VERSION 5.7 ;
  NOWIREEXTENSIONATPIN ON ;
  DIVIDERCHAR "/" ;
  BUSBITCHARS "[]" ;
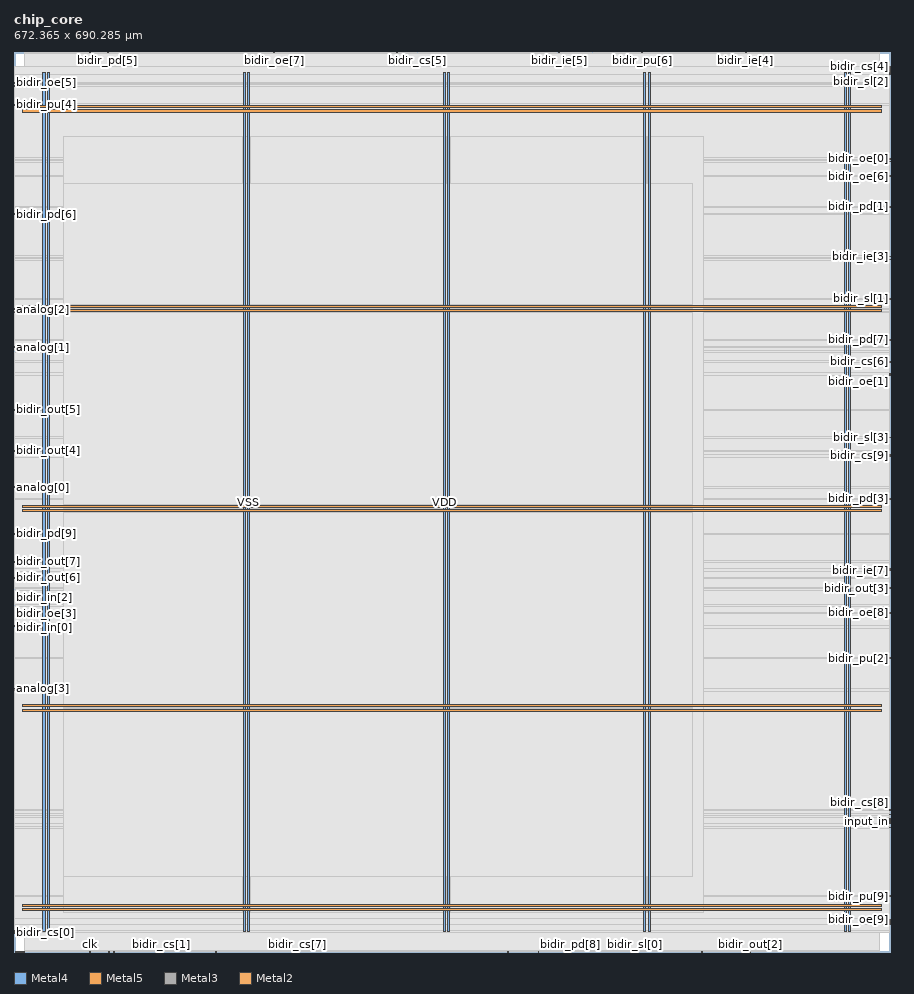
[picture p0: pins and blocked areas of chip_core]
MACRO chip_core
  CLASS BLOCK ;
  FOREIGN chip_core ;
  ORIGIN 0.000 0.000 ;
  SIZE 672.365 BY 690.285 ;
  PIN VDD
    DIRECTION INOUT ;
    USE POWER ;
    PORT
      LAYER Metal4 ;
        RECT 22.240 15.380 23.840 674.540 ;
    END
    PORT
      LAYER Metal4 ;
        RECT 175.840 15.380 177.440 674.540 ;
    END
    PORT
      LAYER Metal4 ;
        RECT 329.440 15.380 331.040 674.540 ;
    END
    PORT
      LAYER Metal4 ;
        RECT 483.040 15.380 484.640 674.540 ;
    END
    PORT
      LAYER Metal4 ;
        RECT 636.640 15.380 638.240 674.540 ;
    END
    PORT
      LAYER Metal5 ;
        RECT 6.720 31.530 665.280 33.130 ;
    END
    PORT
      LAYER Metal5 ;
        RECT 6.720 184.710 665.280 186.310 ;
    END
    PORT
      LAYER Metal5 ;
        RECT 6.720 337.890 665.280 339.490 ;
    END
    PORT
      LAYER Metal5 ;
        RECT 6.720 491.070 665.280 492.670 ;
    END
    PORT
      LAYER Metal5 ;
        RECT 6.720 644.250 665.280 645.850 ;
    END
  END VDD
  PIN VSS
    DIRECTION INOUT ;
    USE GROUND ;
    PORT
      LAYER Metal4 ;
        RECT 25.540 15.380 27.140 674.540 ;
    END
    PORT
      LAYER Metal4 ;
        RECT 179.140 15.380 180.740 674.540 ;
    END
    PORT
      LAYER Metal4 ;
        RECT 332.740 15.380 334.340 674.540 ;
    END
    PORT
      LAYER Metal4 ;
        RECT 486.340 15.380 487.940 674.540 ;
    END
    PORT
      LAYER Metal4 ;
        RECT 639.940 15.380 641.540 674.540 ;
    END
    PORT
      LAYER Metal5 ;
        RECT 6.720 34.830 665.280 36.430 ;
    END
    PORT
      LAYER Metal5 ;
        RECT 6.720 188.010 665.280 189.610 ;
    END
    PORT
      LAYER Metal5 ;
        RECT 6.720 341.190 665.280 342.790 ;
    END
    PORT
      LAYER Metal5 ;
        RECT 6.720 494.370 665.280 495.970 ;
    END
    PORT
      LAYER Metal5 ;
        RECT 6.720 647.550 665.280 649.150 ;
    END
  END VSS
  PIN analog[0]
    DIRECTION INOUT ;
    USE SIGNAL ;
    ANTENNAGATEAREA 1.017500 ;
    PORT
      LAYER Metal3 ;
        RECT 0.000 356.160 0.560 356.720 ;
    END
  END analog[0]
  PIN analog[1]
    DIRECTION INOUT ;
    USE SIGNAL ;
    ANTENNAGATEAREA 1.536500 ;
    ANTENNADIFFAREA 0.893200 ;
    PORT
      LAYER Metal3 ;
        RECT 0.000 463.680 0.560 464.240 ;
    END
  END analog[1]
  PIN analog[2]
    DIRECTION INOUT ;
    USE SIGNAL ;
    ANTENNAGATEAREA 0.894500 ;
    ANTENNADIFFAREA 0.893200 ;
    PORT
      LAYER Metal3 ;
        RECT 0.000 492.800 0.560 493.360 ;
    END
  END analog[2]
  PIN analog[3]
    DIRECTION INOUT ;
    USE SIGNAL ;
    ANTENNAGATEAREA 0.894500 ;
    ANTENNADIFFAREA 0.893200 ;
    PORT
      LAYER Metal3 ;
        RECT 0.000 201.600 0.560 202.160 ;
    END
  END analog[3]
  PIN bidir_cs[0]
    DIRECTION OUTPUT ;
    USE SIGNAL ;
    ANTENNADIFFAREA 0.536800 ;
    PORT
      LAYER Metal3 ;
        RECT 0.000 14.560 0.560 15.120 ;
    END
  END bidir_cs[0]
  PIN bidir_cs[1]
    DIRECTION OUTPUT ;
    USE SIGNAL ;
    ANTENNADIFFAREA 0.536800 ;
    PORT
      LAYER Metal2 ;
        RECT 113.120 0.000 113.680 0.560 ;
    END
  END bidir_cs[1]
  PIN bidir_cs[2]
    DIRECTION OUTPUT ;
    USE SIGNAL ;
    ANTENNADIFFAREA 0.536800 ;
    PORT
      LAYER Metal2 ;
        RECT 76.160 0.000 76.720 0.560 ;
    END
  END bidir_cs[2]
  PIN bidir_cs[3]
    DIRECTION OUTPUT ;
    USE SIGNAL ;
    ANTENNADIFFAREA 0.360800 ;
    PORT
      LAYER Metal3 ;
        RECT 671.805 101.920 672.365 102.480 ;
    END
  END bidir_cs[3]
  PIN bidir_cs[4]
    DIRECTION OUTPUT ;
    USE SIGNAL ;
    ANTENNADIFFAREA 0.360800 ;
    PORT
      LAYER Metal3 ;
        RECT 671.805 678.720 672.365 679.280 ;
    END
  END bidir_cs[4]
  PIN bidir_cs[5]
    DIRECTION OUTPUT ;
    USE SIGNAL ;
    ANTENNADIFFAREA 0.360800 ;
    PORT
      LAYER Metal2 ;
        RECT 309.120 689.725 309.680 690.285 ;
    END
  END bidir_cs[5]
  PIN bidir_cs[6]
    DIRECTION OUTPUT ;
    USE SIGNAL ;
    ANTENNADIFFAREA 0.360800 ;
    PORT
      LAYER Metal3 ;
        RECT 671.805 452.480 672.365 453.040 ;
    END
  END bidir_cs[6]
  PIN bidir_cs[7]
    DIRECTION OUTPUT ;
    USE SIGNAL ;
    ANTENNADIFFAREA 0.360800 ;
    PORT
      LAYER Metal2 ;
        RECT 217.280 0.000 217.840 0.560 ;
    END
  END bidir_cs[7]
  PIN bidir_cs[8]
    DIRECTION OUTPUT ;
    USE SIGNAL ;
    ANTENNADIFFAREA 0.360800 ;
    PORT
      LAYER Metal3 ;
        RECT 671.805 108.640 672.365 109.200 ;
    END
  END bidir_cs[8]
  PIN bidir_cs[9]
    DIRECTION OUTPUT ;
    USE SIGNAL ;
    ANTENNADIFFAREA 0.360800 ;
    PORT
      LAYER Metal3 ;
        RECT 671.805 380.800 672.365 381.360 ;
    END
  END bidir_cs[9]
  PIN bidir_ie[0]
    DIRECTION OUTPUT ;
    USE SIGNAL ;
    ANTENNADIFFAREA 0.536800 ;
    PORT
      LAYER Metal3 ;
        RECT 671.805 95.200 672.365 95.760 ;
    END
  END bidir_ie[0]
  PIN bidir_ie[1]
    DIRECTION OUTPUT ;
    USE SIGNAL ;
    ANTENNADIFFAREA 0.536800 ;
    PORT
      LAYER Metal2 ;
        RECT 58.240 689.725 58.800 690.285 ;
    END
  END bidir_ie[1]
  PIN bidir_ie[2]
    DIRECTION OUTPUT ;
    USE SIGNAL ;
    ANTENNADIFFAREA 0.536800 ;
    PORT
      LAYER Metal3 ;
        RECT 671.805 105.280 672.365 105.840 ;
    END
  END bidir_ie[2]
  PIN bidir_ie[3]
    DIRECTION OUTPUT ;
    USE SIGNAL ;
    ANTENNADIFFAREA 0.360800 ;
    PORT
      LAYER Metal3 ;
        RECT 671.805 533.120 672.365 533.680 ;
    END
  END bidir_ie[3]
  PIN bidir_ie[4]
    DIRECTION OUTPUT ;
    USE SIGNAL ;
    ANTENNADIFFAREA 0.360800 ;
    PORT
      LAYER Metal2 ;
        RECT 561.120 689.725 561.680 690.285 ;
    END
  END bidir_ie[4]
  PIN bidir_ie[5]
    DIRECTION OUTPUT ;
    USE SIGNAL ;
    ANTENNADIFFAREA 0.360800 ;
    PORT
      LAYER Metal2 ;
        RECT 417.760 689.725 418.320 690.285 ;
    END
  END bidir_ie[5]
  PIN bidir_ie[6]
    DIRECTION OUTPUT ;
    USE SIGNAL ;
    ANTENNADIFFAREA 0.360800 ;
    PORT
      LAYER Metal2 ;
        RECT 443.520 689.725 444.080 690.285 ;
    END
  END bidir_ie[6]
  PIN bidir_ie[7]
    DIRECTION OUTPUT ;
    USE SIGNAL ;
    ANTENNADIFFAREA 0.360800 ;
    PORT
      LAYER Metal3 ;
        RECT 671.805 292.320 672.365 292.880 ;
    END
  END bidir_ie[7]
  PIN bidir_ie[8]
    DIRECTION OUTPUT ;
    USE SIGNAL ;
    ANTENNADIFFAREA 0.360800 ;
    PORT
      LAYER Metal3 ;
        RECT 671.805 293.440 672.365 294.000 ;
    END
  END bidir_ie[8]
  PIN bidir_ie[9]
    DIRECTION OUTPUT ;
    USE SIGNAL ;
    ANTENNADIFFAREA 0.360800 ;
    PORT
      LAYER Metal3 ;
        RECT 671.805 379.680 672.365 380.240 ;
    END
  END bidir_ie[9]
  PIN bidir_in[0]
    DIRECTION INPUT ;
    USE SIGNAL ;
    ANTENNAGATEAREA 0.498500 ;
    PORT
      LAYER Metal3 ;
        RECT 0.000 248.640 0.560 249.200 ;
    END
  END bidir_in[0]
  PIN bidir_in[1]
    DIRECTION INPUT ;
    USE SIGNAL ;
    ANTENNAGATEAREA 0.498500 ;
    PORT
      LAYER Metal3 ;
        RECT 0.000 249.760 0.560 250.320 ;
    END
  END bidir_in[1]
  PIN bidir_in[2]
    DIRECTION INPUT ;
    USE SIGNAL ;
    ANTENNAGATEAREA 0.498500 ;
    PORT
      LAYER Metal3 ;
        RECT 0.000 277.760 0.560 278.320 ;
    END
  END bidir_in[2]
  PIN bidir_in[3]
    DIRECTION INPUT ;
    USE SIGNAL ;
    PORT
      LAYER Metal2 ;
        RECT 1.120 0.000 1.680 0.560 ;
    END
  END bidir_in[3]
  PIN bidir_in[4]
    DIRECTION INPUT ;
    USE SIGNAL ;
    PORT
      LAYER Metal2 ;
        RECT 2.240 0.000 2.800 0.560 ;
    END
  END bidir_in[4]
  PIN bidir_in[5]
    DIRECTION INPUT ;
    USE SIGNAL ;
    PORT
      LAYER Metal2 ;
        RECT 3.360 0.000 3.920 0.560 ;
    END
  END bidir_in[5]
  PIN bidir_in[6]
    DIRECTION INPUT ;
    USE SIGNAL ;
    PORT
      LAYER Metal2 ;
        RECT 4.480 0.000 5.040 0.560 ;
    END
  END bidir_in[6]
  PIN bidir_in[7]
    DIRECTION INPUT ;
    USE SIGNAL ;
    PORT
      LAYER Metal2 ;
        RECT 5.600 0.000 6.160 0.560 ;
    END
  END bidir_in[7]
  PIN bidir_in[8]
    DIRECTION INPUT ;
    USE SIGNAL ;
    PORT
      LAYER Metal2 ;
        RECT 6.720 0.000 7.280 0.560 ;
    END
  END bidir_in[8]
  PIN bidir_in[9]
    DIRECTION INPUT ;
    USE SIGNAL ;
    PORT
      LAYER Metal2 ;
        RECT 7.840 0.000 8.400 0.560 ;
    END
  END bidir_in[9]
  PIN bidir_oe[0]
    DIRECTION OUTPUT ;
    USE SIGNAL ;
    ANTENNADIFFAREA 0.360800 ;
    PORT
      LAYER Metal3 ;
        RECT 671.805 608.160 672.365 608.720 ;
    END
  END bidir_oe[0]
  PIN bidir_oe[1]
    DIRECTION OUTPUT ;
    USE SIGNAL ;
    ANTENNADIFFAREA 0.360800 ;
    PORT
      LAYER Metal3 ;
        RECT 671.805 443.520 672.365 444.080 ;
    END
  END bidir_oe[1]
  PIN bidir_oe[2]
    DIRECTION OUTPUT ;
    USE SIGNAL ;
    ANTENNADIFFAREA 0.360800 ;
    PORT
      LAYER Metal3 ;
        RECT 671.805 605.920 672.365 606.480 ;
    END
  END bidir_oe[2]
  PIN bidir_oe[3]
    DIRECTION OUTPUT ;
    USE SIGNAL ;
    ANTENNADIFFAREA 0.897600 ;
    PORT
      LAYER Metal3 ;
        RECT 0.000 265.440 0.560 266.000 ;
    END
  END bidir_oe[3]
  PIN bidir_oe[4]
    DIRECTION OUTPUT ;
    USE SIGNAL ;
    ANTENNADIFFAREA 0.536800 ;
    PORT
      LAYER Metal3 ;
        RECT 671.805 674.240 672.365 674.800 ;
    END
  END bidir_oe[4]
  PIN bidir_oe[5]
    DIRECTION OUTPUT ;
    USE SIGNAL ;
    ANTENNADIFFAREA 0.536800 ;
    PORT
      LAYER Metal3 ;
        RECT 0.000 666.400 0.560 666.960 ;
    END
  END bidir_oe[5]
  PIN bidir_oe[6]
    DIRECTION OUTPUT ;
    USE SIGNAL ;
    ANTENNADIFFAREA 0.536800 ;
    PORT
      LAYER Metal3 ;
        RECT 671.805 594.720 672.365 595.280 ;
    END
  END bidir_oe[6]
  PIN bidir_oe[7]
    DIRECTION OUTPUT ;
    USE SIGNAL ;
    ANTENNADIFFAREA 0.536800 ;
    PORT
      LAYER Metal2 ;
        RECT 199.360 689.725 199.920 690.285 ;
    END
  END bidir_oe[7]
  PIN bidir_oe[8]
    DIRECTION OUTPUT ;
    USE SIGNAL ;
    ANTENNADIFFAREA 0.536800 ;
    PORT
      LAYER Metal3 ;
        RECT 671.805 259.840 672.365 260.400 ;
    END
  END bidir_oe[8]
  PIN bidir_oe[9]
    DIRECTION OUTPUT ;
    USE SIGNAL ;
    ANTENNADIFFAREA 0.536800 ;
    PORT
      LAYER Metal3 ;
        RECT 671.805 24.640 672.365 25.200 ;
    END
  END bidir_oe[9]
  PIN bidir_out[0]
    DIRECTION OUTPUT ;
    USE SIGNAL ;
    ANTENNADIFFAREA 0.897600 ;
    PORT
      LAYER Metal3 ;
        RECT 671.805 98.560 672.365 99.120 ;
    END
  END bidir_out[0]
  PIN bidir_out[1]
    DIRECTION OUTPUT ;
    USE SIGNAL ;
    ANTENNADIFFAREA 0.897600 ;
    PORT
      LAYER Metal3 ;
        RECT 671.805 100.800 672.365 101.360 ;
    END
  END bidir_out[1]
  PIN bidir_out[2]
    DIRECTION OUTPUT ;
    USE SIGNAL ;
    ANTENNADIFFAREA 0.897600 ;
    PORT
      LAYER Metal2 ;
        RECT 564.480 0.000 565.040 0.560 ;
    END
  END bidir_out[2]
  PIN bidir_out[3]
    DIRECTION OUTPUT ;
    USE SIGNAL ;
    ANTENNADIFFAREA 0.897600 ;
    PORT
      LAYER Metal3 ;
        RECT 671.805 278.880 672.365 279.440 ;
    END
  END bidir_out[3]
  PIN bidir_out[4]
    DIRECTION OUTPUT ;
    USE SIGNAL ;
    ANTENNADIFFAREA 0.897600 ;
    PORT
      LAYER Metal3 ;
        RECT 0.000 384.160 0.560 384.720 ;
    END
  END bidir_out[4]
  PIN bidir_out[5]
    DIRECTION OUTPUT ;
    USE SIGNAL ;
    ANTENNADIFFAREA 0.897600 ;
    PORT
      LAYER Metal3 ;
        RECT 0.000 415.520 0.560 416.080 ;
    END
  END bidir_out[5]
  PIN bidir_out[6]
    DIRECTION OUTPUT ;
    USE SIGNAL ;
    ANTENNADIFFAREA 0.897600 ;
    PORT
      LAYER Metal3 ;
        RECT 0.000 286.720 0.560 287.280 ;
    END
  END bidir_out[6]
  PIN bidir_out[7]
    DIRECTION OUTPUT ;
    USE SIGNAL ;
    ANTENNADIFFAREA 0.897600 ;
    PORT
      LAYER Metal3 ;
        RECT 0.000 299.040 0.560 299.600 ;
    END
  END bidir_out[7]
  PIN bidir_out[8]
    DIRECTION OUTPUT ;
    USE SIGNAL ;
    ANTENNADIFFAREA 0.897600 ;
    PORT
      LAYER Metal3 ;
        RECT 0.000 490.560 0.560 491.120 ;
    END
  END bidir_out[8]
  PIN bidir_out[9]
    DIRECTION OUTPUT ;
    USE SIGNAL ;
    ANTENNADIFFAREA 0.897600 ;
    PORT
      LAYER Metal3 ;
        RECT 0.000 200.480 0.560 201.040 ;
    END
  END bidir_out[9]
  PIN bidir_pd[0]
    DIRECTION OUTPUT ;
    USE SIGNAL ;
    ANTENNADIFFAREA 0.360800 ;
    PORT
      LAYER Metal2 ;
        RECT 527.520 0.000 528.080 0.560 ;
    END
  END bidir_pd[0]
  PIN bidir_pd[1]
    DIRECTION OUTPUT ;
    USE SIGNAL ;
    ANTENNADIFFAREA 0.360800 ;
    PORT
      LAYER Metal3 ;
        RECT 671.805 571.200 672.365 571.760 ;
    END
  END bidir_pd[1]
  PIN bidir_pd[2]
    DIRECTION OUTPUT ;
    USE SIGNAL ;
    ANTENNADIFFAREA 0.360800 ;
    PORT
      LAYER Metal3 ;
        RECT 671.805 676.480 672.365 677.040 ;
    END
  END bidir_pd[2]
  PIN bidir_pd[3]
    DIRECTION OUTPUT ;
    USE SIGNAL ;
    ANTENNADIFFAREA 0.360800 ;
    PORT
      LAYER Metal3 ;
        RECT 671.805 347.200 672.365 347.760 ;
    END
  END bidir_pd[3]
  PIN bidir_pd[4]
    DIRECTION OUTPUT ;
    USE SIGNAL ;
    ANTENNADIFFAREA 0.360800 ;
    PORT
      LAYER Metal3 ;
        RECT 0.000 460.320 0.560 460.880 ;
    END
  END bidir_pd[4]
  PIN bidir_pd[5]
    DIRECTION OUTPUT ;
    USE SIGNAL ;
    ANTENNADIFFAREA 0.360800 ;
    PORT
      LAYER Metal2 ;
        RECT 71.680 689.725 72.240 690.285 ;
    END
  END bidir_pd[5]
  PIN bidir_pd[6]
    DIRECTION OUTPUT ;
    USE SIGNAL ;
    ANTENNADIFFAREA 0.360800 ;
    PORT
      LAYER Metal3 ;
        RECT 0.000 565.600 0.560 566.160 ;
    END
  END bidir_pd[6]
  PIN bidir_pd[7]
    DIRECTION OUTPUT ;
    USE SIGNAL ;
    ANTENNADIFFAREA 0.360800 ;
    PORT
      LAYER Metal3 ;
        RECT 671.805 469.280 672.365 469.840 ;
    END
  END bidir_pd[7]
  PIN bidir_pd[8]
    DIRECTION OUTPUT ;
    USE SIGNAL ;
    ANTENNADIFFAREA 0.360800 ;
    PORT
      LAYER Metal2 ;
        RECT 426.720 0.000 427.280 0.560 ;
    END
  END bidir_pd[8]
  PIN bidir_pd[9]
    DIRECTION OUTPUT ;
    USE SIGNAL ;
    ANTENNADIFFAREA 0.360800 ;
    PORT
      LAYER Metal3 ;
        RECT 0.000 320.320 0.560 320.880 ;
    END
  END bidir_pd[9]
  PIN bidir_pu[0]
    DIRECTION OUTPUT ;
    USE SIGNAL ;
    ANTENNADIFFAREA 0.536800 ;
    PORT
      LAYER Metal3 ;
        RECT 671.805 23.520 672.365 24.080 ;
    END
  END bidir_pu[0]
  PIN bidir_pu[1]
    DIRECTION OUTPUT ;
    USE SIGNAL ;
    ANTENNADIFFAREA 0.360800 ;
    PORT
      LAYER Metal2 ;
        RECT 402.080 0.000 402.640 0.560 ;
    END
  END bidir_pu[1]
  PIN bidir_pu[2]
    DIRECTION OUTPUT ;
    USE SIGNAL ;
    ANTENNADIFFAREA 0.360800 ;
    PORT
      LAYER Metal3 ;
        RECT 671.805 225.120 672.365 225.680 ;
    END
  END bidir_pu[2]
  PIN bidir_pu[3]
    DIRECTION OUTPUT ;
    USE SIGNAL ;
    ANTENNADIFFAREA 0.360800 ;
    PORT
      LAYER Metal3 ;
        RECT 671.805 675.360 672.365 675.920 ;
    END
  END bidir_pu[3]
  PIN bidir_pu[4]
    DIRECTION OUTPUT ;
    USE SIGNAL ;
    ANTENNADIFFAREA 0.360800 ;
    PORT
      LAYER Metal3 ;
        RECT 0.000 649.600 0.560 650.160 ;
    END
  END bidir_pu[4]
  PIN bidir_pu[5]
    DIRECTION OUTPUT ;
    USE SIGNAL ;
    ANTENNADIFFAREA 0.360800 ;
    PORT
      LAYER Metal2 ;
        RECT 416.640 689.725 417.200 690.285 ;
    END
  END bidir_pu[5]
  PIN bidir_pu[6]
    DIRECTION OUTPUT ;
    USE SIGNAL ;
    ANTENNADIFFAREA 0.360800 ;
    PORT
      LAYER Metal2 ;
        RECT 481.600 689.725 482.160 690.285 ;
    END
  END bidir_pu[6]
  PIN bidir_pu[7]
    DIRECTION OUTPUT ;
    USE SIGNAL ;
    ANTENNADIFFAREA 0.360800 ;
    PORT
      LAYER Metal2 ;
        RECT 293.440 689.725 294.000 690.285 ;
    END
  END bidir_pu[7]
  PIN bidir_pu[8]
    DIRECTION OUTPUT ;
    USE SIGNAL ;
    ANTENNADIFFAREA 0.360800 ;
    PORT
      LAYER Metal2 ;
        RECT 378.560 0.000 379.120 0.560 ;
    END
  END bidir_pu[8]
  PIN bidir_pu[9]
    DIRECTION OUTPUT ;
    USE SIGNAL ;
    ANTENNADIFFAREA 0.360800 ;
    PORT
      LAYER Metal3 ;
        RECT 671.805 42.560 672.365 43.120 ;
    END
  END bidir_pu[9]
  PIN bidir_sl[0]
    DIRECTION OUTPUT ;
    USE SIGNAL ;
    ANTENNADIFFAREA 0.360800 ;
    PORT
      LAYER Metal2 ;
        RECT 476.000 0.000 476.560 0.560 ;
    END
  END bidir_sl[0]
  PIN bidir_sl[1]
    DIRECTION OUTPUT ;
    USE SIGNAL ;
    ANTENNADIFFAREA 0.360800 ;
    PORT
      LAYER Metal3 ;
        RECT 671.805 500.640 672.365 501.200 ;
    END
  END bidir_sl[1]
  PIN bidir_sl[2]
    DIRECTION OUTPUT ;
    USE SIGNAL ;
    ANTENNADIFFAREA 0.360800 ;
    PORT
      LAYER Metal3 ;
        RECT 671.805 673.120 672.365 673.680 ;
    END
  END bidir_sl[2]
  PIN bidir_sl[3]
    DIRECTION OUTPUT ;
    USE SIGNAL ;
    ANTENNADIFFAREA 0.536800 ;
    PORT
      LAYER Metal3 ;
        RECT 671.805 394.240 672.365 394.800 ;
    END
  END bidir_sl[3]
  PIN bidir_sl[4]
    DIRECTION OUTPUT ;
    USE SIGNAL ;
    ANTENNADIFFAREA 0.360800 ;
    PORT
      LAYER Metal3 ;
        RECT 0.000 664.160 0.560 664.720 ;
    END
  END bidir_sl[4]
  PIN bidir_sl[5]
    DIRECTION OUTPUT ;
    USE SIGNAL ;
    ANTENNADIFFAREA 0.360800 ;
    PORT
      LAYER Metal3 ;
        RECT 671.805 677.600 672.365 678.160 ;
    END
  END bidir_sl[5]
  PIN bidir_sl[6]
    DIRECTION OUTPUT ;
    USE SIGNAL ;
    ANTENNADIFFAREA 0.360800 ;
    PORT
      LAYER Metal3 ;
        RECT 671.805 530.880 672.365 531.440 ;
    END
  END bidir_sl[6]
  PIN bidir_sl[7]
    DIRECTION OUTPUT ;
    USE SIGNAL ;
    ANTENNADIFFAREA 0.360800 ;
    PORT
      LAYER Metal2 ;
        RECT 154.560 0.000 155.120 0.560 ;
    END
  END bidir_sl[7]
  PIN bidir_sl[8]
    DIRECTION OUTPUT ;
    USE SIGNAL ;
    ANTENNADIFFAREA 0.360800 ;
    PORT
      LAYER Metal3 ;
        RECT 671.805 21.280 672.365 21.840 ;
    END
  END bidir_sl[8]
  PIN bidir_sl[9]
    DIRECTION OUTPUT ;
    USE SIGNAL ;
    ANTENNADIFFAREA 0.360800 ;
    PORT
      LAYER Metal3 ;
        RECT 671.805 22.400 672.365 22.960 ;
    END
  END bidir_sl[9]
  PIN clk
    DIRECTION INPUT ;
    USE SIGNAL ;
    ANTENNAGATEAREA 4.738000 ;
    PORT
      LAYER Metal2 ;
        RECT 58.240 0.000 58.800 0.560 ;
    END
  END clk
  PIN input_in
    DIRECTION INPUT ;
    USE SIGNAL ;
    ANTENNAGATEAREA 0.498500 ;
    PORT
      LAYER Metal3 ;
        RECT 671.805 99.680 672.365 100.240 ;
    END
  END input_in
  PIN input_pd
    DIRECTION OUTPUT ;
    USE SIGNAL ;
    ANTENNADIFFAREA 0.360800 ;
    PORT
      LAYER Metal3 ;
        RECT 671.805 442.400 672.365 442.960 ;
    END
  END input_pd
  PIN input_pu
    DIRECTION OUTPUT ;
    USE SIGNAL ;
    ANTENNADIFFAREA 0.360800 ;
    PORT
      LAYER Metal3 ;
        RECT 0.000 15.680 0.560 16.240 ;
    END
  END input_pu
  PIN rst_n
    DIRECTION INPUT ;
    USE SIGNAL ;
    ANTENNAGATEAREA 0.498500 ;
    PORT
      LAYER Metal2 ;
        RECT 72.800 0.000 73.360 0.560 ;
    END
  END rst_n
  OBS
      LAYER Nwell ;
        RECT 6.290 15.250 665.710 674.670 ;
      LAYER Metal1 ;
        RECT 6.720 15.380 665.280 674.540 ;
      LAYER Metal2 ;
        RECT 7.980 689.425 57.940 689.725 ;
        RECT 59.100 689.425 71.380 689.725 ;
        RECT 72.540 689.425 199.060 689.725 ;
        RECT 200.220 689.425 293.140 689.725 ;
        RECT 294.300 689.425 308.820 689.725 ;
        RECT 309.980 689.425 416.340 689.725 ;
        RECT 418.620 689.425 443.220 689.725 ;
        RECT 444.380 689.425 481.300 689.725 ;
        RECT 482.460 689.425 560.820 689.725 ;
        RECT 561.980 689.425 663.460 689.725 ;
        RECT 7.980 0.860 663.460 689.425 ;
        RECT 8.700 0.560 57.940 0.860 ;
        RECT 59.100 0.560 72.500 0.860 ;
        RECT 73.660 0.560 75.860 0.860 ;
        RECT 77.020 0.560 112.820 0.860 ;
        RECT 113.980 0.560 154.260 0.860 ;
        RECT 155.420 0.560 216.980 0.860 ;
        RECT 218.140 0.560 378.260 0.860 ;
        RECT 379.420 0.560 401.780 0.860 ;
        RECT 402.940 0.560 426.420 0.860 ;
        RECT 427.580 0.560 475.700 0.860 ;
        RECT 476.860 0.560 527.220 0.860 ;
        RECT 528.380 0.560 564.180 0.860 ;
        RECT 565.340 0.560 663.460 0.860 ;
      LAYER Metal3 ;
        RECT 0.560 672.820 671.505 679.140 ;
        RECT 0.560 667.260 671.805 672.820 ;
        RECT 0.860 666.100 671.805 667.260 ;
        RECT 0.560 665.020 671.805 666.100 ;
        RECT 0.860 663.860 671.805 665.020 ;
        RECT 0.560 650.460 671.805 663.860 ;
        RECT 0.860 649.300 671.805 650.460 ;
        RECT 0.560 609.020 671.805 649.300 ;
        RECT 0.560 607.860 671.505 609.020 ;
        RECT 0.560 606.780 671.805 607.860 ;
        RECT 0.560 605.620 671.505 606.780 ;
        RECT 0.560 595.580 671.805 605.620 ;
        RECT 0.560 594.420 671.505 595.580 ;
        RECT 0.560 572.060 671.805 594.420 ;
        RECT 0.560 570.900 671.505 572.060 ;
        RECT 0.560 566.460 671.805 570.900 ;
        RECT 0.860 565.300 671.805 566.460 ;
        RECT 0.560 533.980 671.805 565.300 ;
        RECT 0.560 532.820 671.505 533.980 ;
        RECT 0.560 531.740 671.805 532.820 ;
        RECT 0.560 530.580 671.505 531.740 ;
        RECT 0.560 501.500 671.805 530.580 ;
        RECT 0.560 500.340 671.505 501.500 ;
        RECT 0.560 493.660 671.805 500.340 ;
        RECT 0.860 492.500 671.805 493.660 ;
        RECT 0.560 491.420 671.805 492.500 ;
        RECT 0.860 490.260 671.805 491.420 ;
        RECT 0.560 470.140 671.805 490.260 ;
        RECT 0.560 468.980 671.505 470.140 ;
        RECT 0.560 464.540 671.805 468.980 ;
        RECT 0.860 463.380 671.805 464.540 ;
        RECT 0.560 461.180 671.805 463.380 ;
        RECT 0.860 460.020 671.805 461.180 ;
        RECT 0.560 453.340 671.805 460.020 ;
        RECT 0.560 452.180 671.505 453.340 ;
        RECT 0.560 444.380 671.805 452.180 ;
        RECT 0.560 442.100 671.505 444.380 ;
        RECT 0.560 416.380 671.805 442.100 ;
        RECT 0.860 415.220 671.805 416.380 ;
        RECT 0.560 395.100 671.805 415.220 ;
        RECT 0.560 393.940 671.505 395.100 ;
        RECT 0.560 385.020 671.805 393.940 ;
        RECT 0.860 383.860 671.805 385.020 ;
        RECT 0.560 381.660 671.805 383.860 ;
        RECT 0.560 379.380 671.505 381.660 ;
        RECT 0.560 357.020 671.805 379.380 ;
        RECT 0.860 355.860 671.805 357.020 ;
        RECT 0.560 348.060 671.805 355.860 ;
        RECT 0.560 346.900 671.505 348.060 ;
        RECT 0.560 321.180 671.805 346.900 ;
        RECT 0.860 320.020 671.805 321.180 ;
        RECT 0.560 299.900 671.805 320.020 ;
        RECT 0.860 298.740 671.805 299.900 ;
        RECT 0.560 294.300 671.805 298.740 ;
        RECT 0.560 292.020 671.505 294.300 ;
        RECT 0.560 287.580 671.805 292.020 ;
        RECT 0.860 286.420 671.805 287.580 ;
        RECT 0.560 279.740 671.805 286.420 ;
        RECT 0.560 278.620 671.505 279.740 ;
        RECT 0.860 278.580 671.505 278.620 ;
        RECT 0.860 277.460 671.805 278.580 ;
        RECT 0.560 266.300 671.805 277.460 ;
        RECT 0.860 265.140 671.805 266.300 ;
        RECT 0.560 260.700 671.805 265.140 ;
        RECT 0.560 259.540 671.505 260.700 ;
        RECT 0.560 250.620 671.805 259.540 ;
        RECT 0.860 248.340 671.805 250.620 ;
        RECT 0.560 225.980 671.805 248.340 ;
        RECT 0.560 224.820 671.505 225.980 ;
        RECT 0.560 202.460 671.805 224.820 ;
        RECT 0.860 200.180 671.805 202.460 ;
        RECT 0.560 109.500 671.805 200.180 ;
        RECT 0.560 108.340 671.505 109.500 ;
        RECT 0.560 106.140 671.805 108.340 ;
        RECT 0.560 104.980 671.505 106.140 ;
        RECT 0.560 102.780 671.805 104.980 ;
        RECT 0.560 98.260 671.505 102.780 ;
        RECT 0.560 96.060 671.805 98.260 ;
        RECT 0.560 94.900 671.505 96.060 ;
        RECT 0.560 43.420 671.805 94.900 ;
        RECT 0.560 42.260 671.505 43.420 ;
        RECT 0.560 25.500 671.805 42.260 ;
        RECT 0.560 20.980 671.505 25.500 ;
        RECT 0.560 16.540 671.805 20.980 ;
        RECT 0.860 14.700 671.805 16.540 ;
      LAYER Metal4 ;
        RECT 38.220 30.330 175.540 625.430 ;
        RECT 177.740 30.330 178.840 625.430 ;
        RECT 181.040 30.330 329.140 625.430 ;
        RECT 331.340 30.330 332.440 625.430 ;
        RECT 334.640 30.330 482.740 625.430 ;
        RECT 484.940 30.330 486.040 625.430 ;
        RECT 488.240 30.330 529.060 625.430 ;
      LAYER Metal5 ;
        RECT 38.140 496.570 520.180 589.270 ;
        RECT 38.140 493.270 520.180 493.770 ;
        RECT 38.140 343.390 520.180 490.470 ;
        RECT 38.140 340.090 520.180 340.590 ;
        RECT 38.140 190.210 520.180 337.290 ;
        RECT 38.140 186.910 520.180 187.410 ;
        RECT 38.140 57.830 520.180 184.110 ;
  END
END chip_core
END LIBRARY

